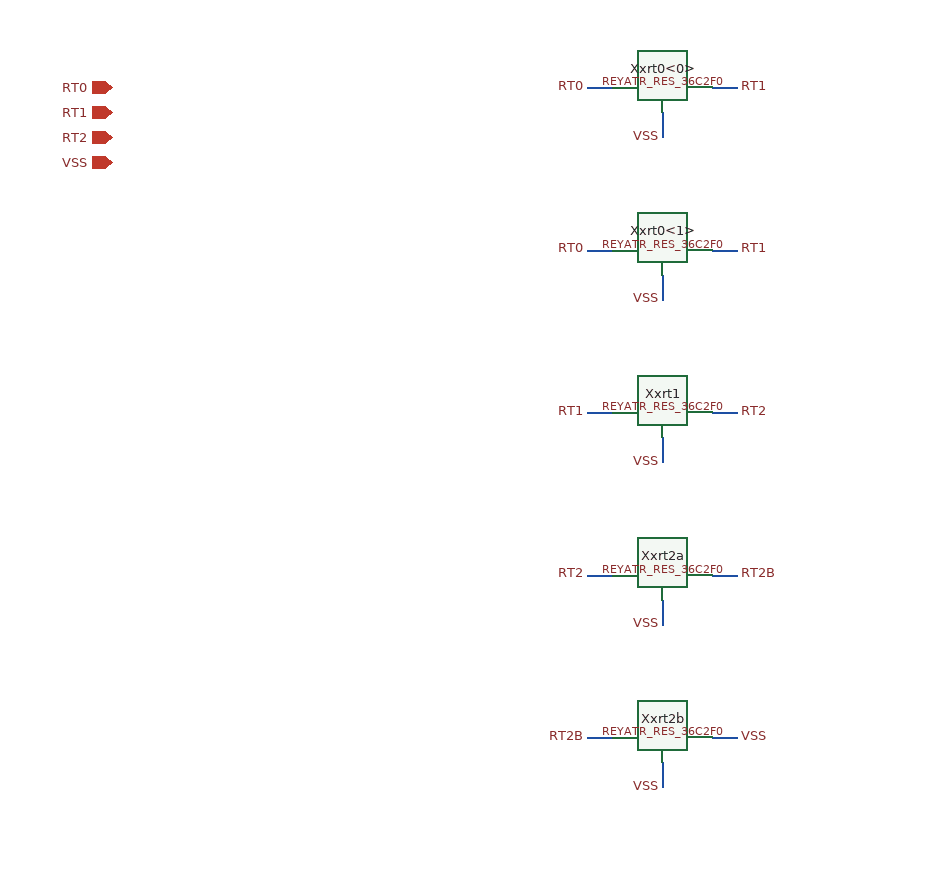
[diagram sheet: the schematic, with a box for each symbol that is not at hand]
v {xschem version=3.0.0 file_version=1.2 }
G {}
K {}
V {}
S {}
E {}
C {devices/iopin.sym} 0 0 0 0 {name=p0 lab=RT0}
C {devices/iopin.sym} 0 20 0 0 {name=p1 lab=RT1}
C {devices/iopin.sym} 0 40 0 0 {name=p2 lab=RT2}
C {devices/iopin.sym} 0 60 0 0 {name=p3 lab=VSS}
C {REY_ATR_SKY130A/REYATR_RES_36C2F0.sym} 400 0 0 0 {name=Xxrt0<0>}
N 500.0 0.0 480.0 0.0 {lab=RT1}
C {devices/lab_pin.sym} 500.0 0.0 2 0 {name=l0 sig_type=std_logic lab=RT1 }
N 380.0 0.0 400.0 0.0 {lab=RT0}
C {devices/lab_pin.sym} 380.0 0.0 0 0 {name=l1 sig_type=std_logic lab=RT0 }
N 440.0 40.0 440.0 20.0 {lab=VSS}
C {devices/lab_pin.sym} 440.0 40.0 1 0 {name=l2 sig_type=std_logic lab=VSS }
C {REY_ATR_SKY130A/REYATR_RES_36C2F0.sym} 400 130 0 0 {name=Xxrt0<1>}
N 500.0 130.0 480.0 130.0 {lab=RT1}
C {devices/lab_pin.sym} 500.0 130.0 2 0 {name=l3 sig_type=std_logic lab=RT1 }
N 380.0 130.0 400.0 130.0 {lab=RT0}
C {devices/lab_pin.sym} 380.0 130.0 0 0 {name=l4 sig_type=std_logic lab=RT0 }
N 440.0 170.0 440.0 150.0 {lab=VSS}
C {devices/lab_pin.sym} 440.0 170.0 1 0 {name=l5 sig_type=std_logic lab=VSS }
C {REY_ATR_SKY130A/REYATR_RES_36C2F0.sym} 400 260 0 0 {name=Xxrt1}
N 500.0 260.0 480.0 260.0 {lab=RT2}
C {devices/lab_pin.sym} 500.0 260.0 2 0 {name=l6 sig_type=std_logic lab=RT2 }
N 380.0 260.0 400.0 260.0 {lab=RT1}
C {devices/lab_pin.sym} 380.0 260.0 0 0 {name=l7 sig_type=std_logic lab=RT1 }
N 440.0 300.0 440.0 280.0 {lab=VSS}
C {devices/lab_pin.sym} 440.0 300.0 1 0 {name=l8 sig_type=std_logic lab=VSS }
C {REY_ATR_SKY130A/REYATR_RES_36C2F0.sym} 400 390 0 0 {name=Xxrt2a}
N 500.0 390.0 480.0 390.0 {lab=RT2B}
C {devices/lab_pin.sym} 500.0 390.0 2 0 {name=l9 sig_type=std_logic lab=RT2B }
N 380.0 390.0 400.0 390.0 {lab=RT2}
C {devices/lab_pin.sym} 380.0 390.0 0 0 {name=l10 sig_type=std_logic lab=RT2 }
N 440.0 430.0 440.0 410.0 {lab=VSS}
C {devices/lab_pin.sym} 440.0 430.0 1 0 {name=l11 sig_type=std_logic lab=VSS }
C {REY_ATR_SKY130A/REYATR_RES_36C2F0.sym} 400 520 0 0 {name=Xxrt2b}
N 500.0 520.0 480.0 520.0 {lab=VSS}
C {devices/lab_pin.sym} 500.0 520.0 2 0 {name=l12 sig_type=std_logic lab=VSS }
N 380.0 520.0 400.0 520.0 {lab=RT2B}
C {devices/lab_pin.sym} 380.0 520.0 0 0 {name=l13 sig_type=std_logic lab=RT2B }
N 440.0 560.0 440.0 540.0 {lab=VSS}
C {devices/lab_pin.sym} 440.0 560.0 1 0 {name=l14 sig_type=std_logic lab=VSS }
